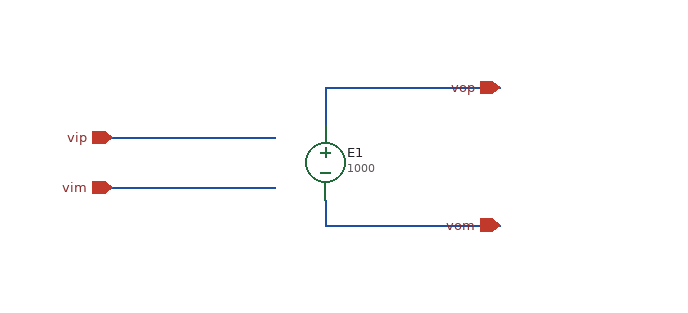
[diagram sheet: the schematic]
v {xschem version=3.4.8RC file_version=1.2}
G {}
K {}
V {}
S {}
E {}
N 0 140 140 140 {lab=vop}
N -0 250 140 250 {lab=vom}
N 0 140 0 170 {lab=vop}
N -0 230 -0 250 {lab=vom}
N -170 180 -40 180 {lab=vip}
N -170 220 -40 220 {lab=xxx}
C {vcvs.sym} 0 200 0 0 {name=E1 value=1000}
C {iopin.sym} 140 140 0 0 {name=p5 lab=vop}
C {iopin.sym} 140 250 0 0 {name=p1 lab=vom}
C {iopin.sym} -170 180 2 0 {name=p2 lab=vip}
C {iopin.sym} -170 220 2 0 {name=p3 lab=vim}
